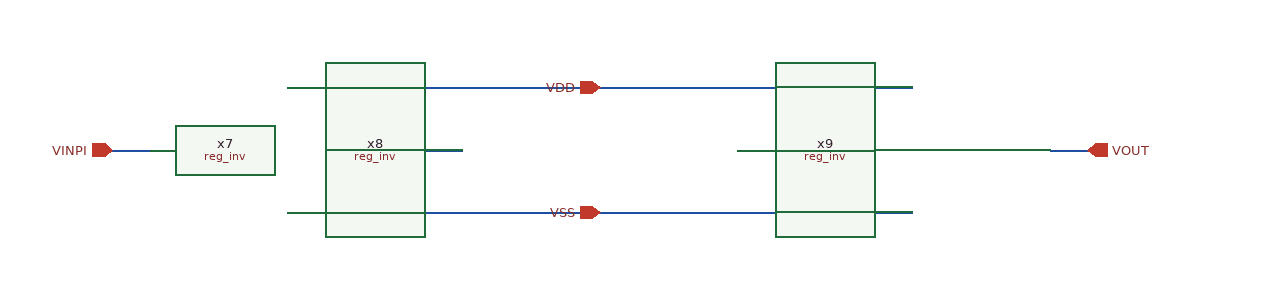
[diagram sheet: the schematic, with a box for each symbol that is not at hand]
v {xschem version=3.4.8RC file_version=1.3}
G {}
K {}
V {}
S {}
F {}
E {}
N 100 -130 130 -130 {lab=VINPI}
N 850 -130 880 -130 {lab=VOUT}
N 240 -80 740 -80 {lab=#net6}
N 240 -180 740 -180 {lab=#net7}
N 350 -130 380 -130 {lab=#net8}
N 600 -130 630 -130 {lab=#net9}
C {reg_inv.sym} 110 -80 0 0 {name=x7}
C {reg_inv.sym} 360 -80 0 0 {name=x8}
C {reg_inv.sym} 610 -80 0 0 {name=x9}
C {iopin.sym} 490 -180 3 0 {name=p15 lab=VDD}
C {iopin.sym} 490 -80 1 0 {name=p16 lab=VSS}
C {iopin.sym} 100 -130 2 0 {name=p18 lab=VINPI}
C {opin.sym} 880 -130 0 0 {name=p17 lab=VOUT}
